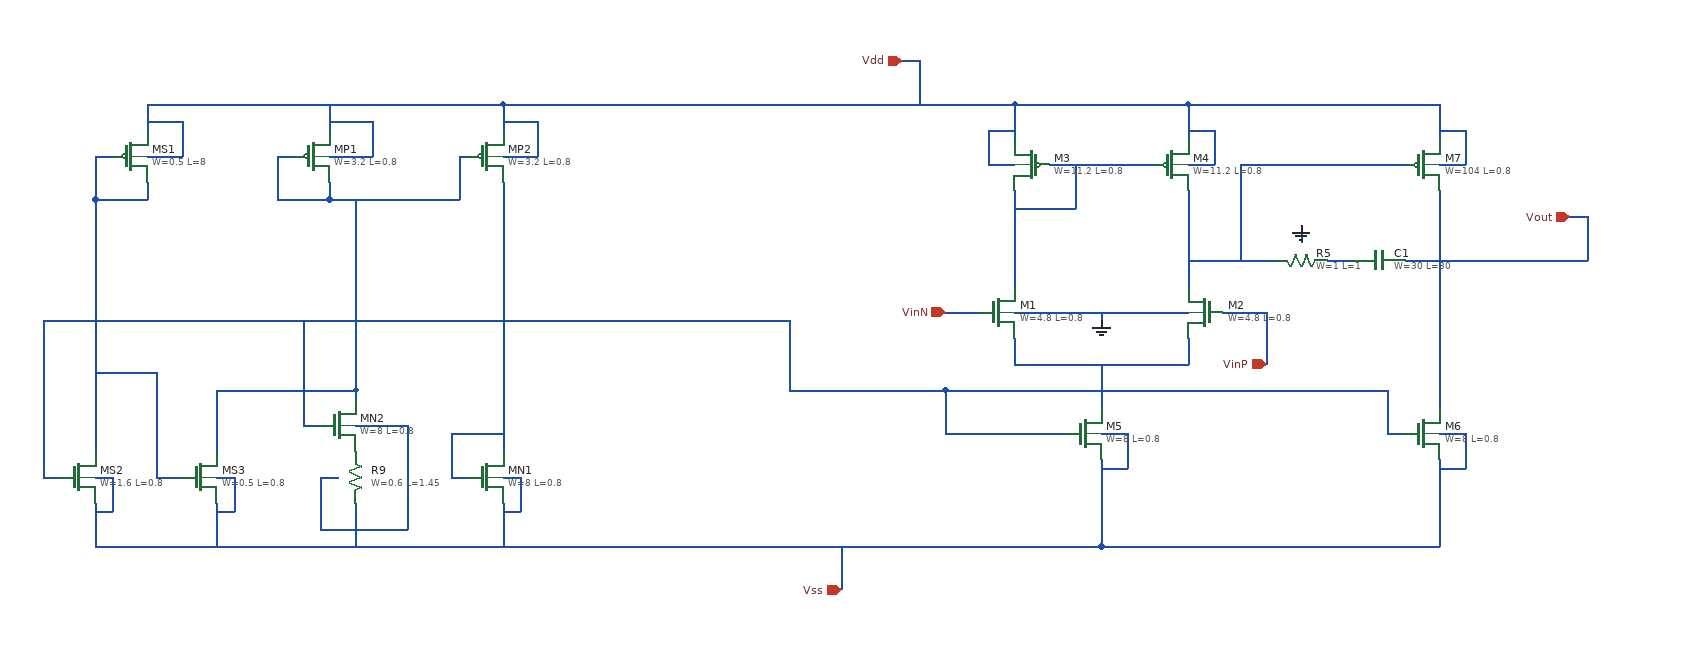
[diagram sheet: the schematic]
v {xschem version=3.4.8RC file_version=1.3}
G {}
K {}
V {}
S {}
F {}
E {}
N 270 0 270 30 {lab=#net1}
N 470 0 470 30 {lab=#net1}
N 360 30 470 30 {lab=#net1}
N 270 30 360 30 {lab=#net1}
N 370 30 370 80 {lab=#net1}
N 270 -170 270 -60 {lab=#net2}
N 470 -170 470 -60 {lab=#net3}
N 270 -270 270 -230 {lab=Vdd}
N 270 -270 470 -270 {lab=Vdd}
N 470 -270 470 -230 {lab=Vdd}
N 470 -270 670 -270 {lab=Vdd}
N 760 -270 760 -230 {lab=Vdd}
N 760 -170 760 80 {lab=Vout}
N 470 -90 570 -90 {lab=#net3}
N 720 -90 760 -90 {lab=Vout}
N 530 -200 630 -200 {lab=#net3}
N 530 -200 530 -90 {lab=#net3}
N 370 140 370 170 {lab=Vdd}
N 760 140 760 170 {lab=Vdd}
N 400 110 400 150 {lab=Vdd}
N 790 110 790 150 {lab=Vdd}
N 190 110 330 110 {lab=#net4}
N 190 70 190 110 {lab=#net4}
N 80 60 190 60 {lab=#net4}
N 190 60 610 60 {lab=#net4}
N 700 70 700 110 {lab=#net4}
N 700 110 720 110 {lab=#net4}
N 190 60 190 70 {lab=#net4}
N 700 60 700 70 {lab=#net4}
N 80 -270 270 -270 {lab=Vdd}
N 190 -30 230 -30 {lab=VinN}
N 510 -30 550 -30 {lab=VinP}
N 310 -200 430 -200 {lab=#net2}
N 340 -200 340 -150 {lab=#net2}
N 270 -150 340 -150 {lab=#net2}
N 240 -200 270 -200 {lab=Vdd}
N 240 -240 240 -200 {lab=Vdd}
N 240 -240 270 -240 {lab=Vdd}
N 470 -200 490 -200 {lab=Vdd}
N 490 -200 500 -200 {lab=Vdd}
N 500 -240 500 -200 {lab=Vdd}
N 470 -240 500 -240 {lab=Vdd}
N 270 -30 290 -30 {lab=0}
N 450 -30 470 -30 {lab=0}
N 760 -200 790 -200 {lab=Vdd}
N 790 -240 790 -200 {lab=Vdd}
N 760 -240 790 -240 {lab=Vdd}
N 370 110 400 110 {lab=Vdd}
N 370 150 400 150 {lab=Vdd}
N 760 110 790 110 {lab=Vdd}
N 760 150 790 150 {lab=Vdd}
N 670 -270 760 -270 {lab=Vdd}
N 610 60 700 60 {lab=#net4}
N 630 -200 720 -200 {lab=#net3}
N 630 -90 660 -90 {lab=#net5}
N 760 -90 930 -90 {lab=Vout}
N 930 -140 930 -90 {lab=Vout}
N 910 -140 930 -140 {lab=Vout}
N -730 -270 -320 -270 {lab=Vdd}
N -730 -270 -730 -240 {lab=Vdd}
N -520 -270 -520 -240 {lab=Vdd}
N -320 -270 -320 -240 {lab=Vdd}
N -730 -210 -690 -210 {lab=Vdd}
N -690 -250 -690 -210 {lab=Vdd}
N -730 -250 -690 -250 {lab=Vdd}
N -520 -210 -470 -210 {lab=Vdd}
N -470 -250 -470 -210 {lab=Vdd}
N -520 -250 -470 -250 {lab=Vdd}
N -320 -210 -280 -210 {lab=Vdd}
N -280 -250 -280 -210 {lab=Vdd}
N -320 -250 -280 -250 {lab=Vdd}
N -790 -210 -770 -210 {lab=#net6}
N -790 -210 -790 -160 {lab=#net6}
N -790 -160 -730 -160 {lab=#net6}
N -730 -180 -730 -160 {lab=#net6}
N -520 -180 -520 -160 {lab=#net7}
N -520 -160 -370 -160 {lab=#net7}
N -370 -210 -370 -160 {lab=#net7}
N -370 -210 -360 -210 {lab=#net7}
N -580 -210 -560 -210 {lab=#net7}
N -580 -210 -580 -160 {lab=#net7}
N -580 -160 -520 -160 {lab=#net7}
N -320 -180 -320 130 {lab=#net4}
N -790 -160 -790 130 {lab=#net6}
N -790 190 -790 240 {lab=Vdd}
N -650 190 -650 240 {lab=Vdd}
N -490 190 -490 240 {lab=Vdd}
N -320 190 -320 240 {lab=Vdd}
N -650 60 -650 130 {lab=#net7}
N -650 60 -490 60 {lab=#net7}
N -490 60 -490 70 {lab=#net7}
N -720 160 -690 160 {lab=#net6}
N -790 40 -720 40 {lab=#net6}
N -850 160 -830 160 {lab=#net4}
N -850 -20 -850 160 {lab=#net4}
N -850 -20 -320 -20 {lab=#net4}
N -550 100 -530 100 {lab=#net4}
N -550 -20 -550 100 {lab=#net4}
N -790 160 -770 160 {lab=Vdd}
N -770 160 -770 200 {lab=Vdd}
N -790 200 -770 200 {lab=Vdd}
N -650 160 -630 160 {lab=Vdd}
N -630 160 -630 200 {lab=Vdd}
N -650 200 -630 200 {lab=Vdd}
N -320 160 -300 160 {lab=Vdd}
N -300 160 -300 200 {lab=Vdd}
N -320 200 -300 200 {lab=Vdd}
N -490 100 -430 100 {lab=Vdd}
N -430 100 -430 220 {lab=Vdd}
N -490 220 -430 220 {lab=Vdd}
N -380 160 -360 160 {lab=#net4}
N -380 110 -380 160 {lab=#net4}
N -380 110 -320 110 {lab=#net4}
N -720 40 -720 160 {lab=#net6}
N -490 -160 -490 60 {lab=#net7}
N -320 -20 10 -20 {lab=#net4}
N 10 10 10 60 {lab=#net4}
N 10 60 80 60 {lab=#net4}
N 600 -130 600 -110 {lab=0}
N -530 160 -510 160 {lab=Vdd}
N -530 160 -530 220 {lab=Vdd}
N -530 220 -490 220 {lab=Vdd}
N 290 -30 450 -30 {lab=0}
N 370 -30 370 -20 {lab=0}
N 140 -320 160 -320 {lab=Vdd}
N 160 -320 160 -270 {lab=Vdd}
N -320 -270 80 -270 {lab=Vdd}
N 10 -20 10 10 {lab=#net4}
N -790 240 370 240 {lab=Vdd}
N 370 170 370 240 {lab=Vdd}
N 370 240 760 240 {lab=Vdd}
N 760 170 760 240 {lab=Vdd}
N 560 -30 560 30 {lab=VinP}
N 550 -30 560 -30 {lab=VinP}
N 70 240 70 290 {lab=Vdd}
C {/foss/pdks/sky130A/libs.tech/xschem/sky130_fd_pr/nfet_01v8_lvt.sym} 250 -30 0 0 {name=M1
W=4.8
L=0.8
nf=1
mult=1
ad="expr('int((@nf + 1)/2) * @W / @nf * 0.29')"
pd="expr('2*int((@nf + 1)/2) * (@W / @nf + 0.29)')"
as="expr('int((@nf + 2)/2) * @W / @nf * 0.29')"
ps="expr('2*int((@nf + 2)/2) * (@W / @nf + 0.29)')"
nrd="expr('0.29 / @W ')" nrs="expr('0.29 / @W ')"
sa=0 sb=0 sd=0
model=nfet_01v8_lvt
spiceprefix=X
}
C {sky130_fd_pr/pfet_01v8.sym} 290 -200 0 1 {name=M3
W=11.2
L=0.8
nf=1
mult=1
ad="expr('int((@nf + 1)/2) * @W / @nf * 0.29')"
pd="expr('2*int((@nf + 1)/2) * (@W / @nf + 0.29)')"
as="expr('int((@nf + 2)/2) * @W / @nf * 0.29')"
ps="expr('2*int((@nf + 2)/2) * (@W / @nf + 0.29)')"
nrd="expr('0.29 / @W ')" nrs="expr('0.29 / @W ')"
sa=0 sb=0 sd=0
model=pfet_01v8
spiceprefix=X
}
C {sky130_fd_pr/nfet_01v8.sym} 350 110 0 0 {name=M5
W=8
L=0.8
nf=1 
mult=3
ad="expr('int((@nf + 1)/2) * @W / @nf * 0.29')"
pd="expr('2*int((@nf + 1)/2) * (@W / @nf + 0.29)')"
as="expr('int((@nf + 2)/2) * @W / @nf * 0.29')"
ps="expr('2*int((@nf + 2)/2) * (@W / @nf + 0.29)')"
nrd="expr('0.29 / @W ')" nrs="expr('0.29 / @W ')"
sa=0 sb=0 sd=0
model=nfet_01v8
spiceprefix=X
}
C {/foss/pdks/sky130A/libs.tech/xschem/sky130_fd_pr/nfet_01v8_lvt.sym} 490 -30 0 1 {name=M2
W=4.8
L=0.8
nf=1
mult=1
ad="expr('int((@nf + 1)/2) * @W / @nf * 0.29')"
pd="expr('2*int((@nf + 1)/2) * (@W / @nf + 0.29)')"
as="expr('int((@nf + 2)/2) * @W / @nf * 0.29')"
ps="expr('2*int((@nf + 2)/2) * (@W / @nf + 0.29)')"
nrd="expr('0.29 / @W ')" nrs="expr('0.29 / @W ')"
sa=0 sb=0 sd=0
model=nfet_01v8_lvt
spiceprefix=X
}
C {sky130_fd_pr/pfet_01v8.sym} 450 -200 0 0 {name=M4
W=11.2
L=0.8
nf=1
mult=1
ad="expr('int((@nf + 1)/2) * @W / @nf * 0.29')"
pd="expr('2*int((@nf + 1)/2) * (@W / @nf + 0.29)')"
as="expr('int((@nf + 2)/2) * @W / @nf * 0.29')"
ps="expr('2*int((@nf + 2)/2) * (@W / @nf + 0.29)')"
nrd="expr('0.29 / @W ')" nrs="expr('0.29 / @W ')"
sa=0 sb=0 sd=0
model=pfet_01v8
spiceprefix=X
}
C {sky130_fd_pr/nfet_01v8.sym} 740 110 0 0 {name=M6
W=8
L=0.8
nf=1
mult=13
ad="expr('int((@nf + 1)/2) * @W / @nf * 0.29')"
pd="expr('2*int((@nf + 1)/2) * (@W / @nf + 0.29)')"
as="expr('int((@nf + 2)/2) * @W / @nf * 0.29')"
ps="expr('2*int((@nf + 2)/2) * (@W / @nf + 0.29)')"
nrd="expr('0.29 / @W ')" nrs="expr('0.29 / @W ')"
sa=0 sb=0 sd=0
model=nfet_01v8
spiceprefix=X
}
C {sky130_fd_pr/pfet_01v8.sym} 740 -200 0 0 {name=M7
W=104
L=0.8
nf=14
mult=1
ad="expr('int((@nf + 1)/2) * @W / @nf * 0.29')"
pd="expr('2*int((@nf + 1)/2) * (@W / @nf + 0.29)')"
as="expr('int((@nf + 2)/2) * @W / @nf * 0.29')"
ps="expr('2*int((@nf + 2)/2) * (@W / @nf + 0.29)')"
nrd="expr('0.29 / @W ')" nrs="expr('0.29 / @W ')"
sa=0 sb=0 sd=0
model=pfet_01v8
spiceprefix=X
}
C {sky130_fd_pr/cap_mim_m3_1.sym} 690 -90 3 0 {name=C1 model=cap_mim_m3_1 W=30 L=30 MF=1 spiceprefix=X}
C {sky130_fd_pr/res_high_po.sym} 600 -90 1 0 {name=R5
W=1
L=1
model=res_high_po
spiceprefix=X
mult=1}
C {sky130_fd_pr/pfet_01v8.sym} -750 -210 0 0 {name=MS1
W=0.5
L=8
nf=1
mult=1
ad="expr('int((@nf + 1)/2) * @W / @nf * 0.29')"
pd="expr('2*int((@nf + 1)/2) * (@W / @nf + 0.29)')"
as="expr('int((@nf + 2)/2) * @W / @nf * 0.29')"
ps="expr('2*int((@nf + 2)/2) * (@W / @nf + 0.29)')"
nrd="expr('0.29 / @W ')" nrs="expr('0.29 / @W ')"
sa=0 sb=0 sd=0
model=pfet_01v8
spiceprefix=X
}
C {sky130_fd_pr/pfet_01v8.sym} -540 -210 0 0 {name=MP1
W=3.2
L=0.8
nf=1
mult=1
ad="expr('int((@nf + 1)/2) * @W / @nf * 0.29')"
pd="expr('2*int((@nf + 1)/2) * (@W / @nf + 0.29)')"
as="expr('int((@nf + 2)/2) * @W / @nf * 0.29')"
ps="expr('2*int((@nf + 2)/2) * (@W / @nf + 0.29)')"
nrd="expr('0.29 / @W ')" nrs="expr('0.29 / @W ')"
sa=0 sb=0 sd=0
model=pfet_01v8
spiceprefix=X
}
C {sky130_fd_pr/pfet_01v8.sym} -340 -210 0 0 {name=MP2
W=3.2
L=0.8
nf=1
mult=1
ad="expr('int((@nf + 1)/2) * @W / @nf * 0.29')"
pd="expr('2*int((@nf + 1)/2) * (@W / @nf + 0.29)')"
as="expr('int((@nf + 2)/2) * @W / @nf * 0.29')"
ps="expr('2*int((@nf + 2)/2) * (@W / @nf + 0.29)')"
nrd="expr('0.29 / @W ')" nrs="expr('0.29 / @W ')"
sa=0 sb=0 sd=0
model=pfet_01v8
spiceprefix=X
}
C {sky130_fd_pr/res_xhigh_po.sym} -490 160 0 0 {name=R9
W=0.6
L=1.45
model=res_xhigh_po
spiceprefix=X
 mult=1}
C {sky130_fd_pr/nfet_01v8.sym} -810 160 0 0 {name=MS2
W=1.6
L=0.8
nf=1 
mult=1
ad="expr('int((@nf + 1)/2) * @W / @nf * 0.29')"
pd="expr('2*int((@nf + 1)/2) * (@W / @nf + 0.29)')"
as="expr('int((@nf + 2)/2) * @W / @nf * 0.29')"
ps="expr('2*int((@nf + 2)/2) * (@W / @nf + 0.29)')"
nrd="expr('0.29 / @W ')" nrs="expr('0.29 / @W ')"
sa=0 sb=0 sd=0
model=nfet_01v8
spiceprefix=X
}
C {sky130_fd_pr/nfet_01v8.sym} -670 160 0 0 {name=MS3
W=0.5
L=0.8
nf=1 
mult=1
ad="expr('int((@nf + 1)/2) * @W / @nf * 0.29')"
pd="expr('2*int((@nf + 1)/2) * (@W / @nf + 0.29)')"
as="expr('int((@nf + 2)/2) * @W / @nf * 0.29')"
ps="expr('2*int((@nf + 2)/2) * (@W / @nf + 0.29)')"
nrd="expr('0.29 / @W ')" nrs="expr('0.29 / @W ')"
sa=0 sb=0 sd=0
model=nfet_01v8
spiceprefix=X
}
C {sky130_fd_pr/nfet_01v8.sym} -510 100 0 0 {name=MN2
W=8
L=0.8
nf=1 
mult=4
ad="expr('int((@nf + 1)/2) * @W / @nf * 0.29')"
pd="expr('2*int((@nf + 1)/2) * (@W / @nf + 0.29)')"
as="expr('int((@nf + 2)/2) * @W / @nf * 0.29')"
ps="expr('2*int((@nf + 2)/2) * (@W / @nf + 0.29)')"
nrd="expr('0.29 / @W ')" nrs="expr('0.29 / @W ')"
sa=0 sb=0 sd=0
model=nfet_01v8
spiceprefix=X
}
C {sky130_fd_pr/nfet_01v8.sym} -340 160 0 0 {name=MN1
W=8
L=0.8
nf=1 
mult=1
ad="expr('int((@nf + 1)/2) * @W / @nf * 0.29')"
pd="expr('2*int((@nf + 1)/2) * (@W / @nf + 0.29)')"
as="expr('int((@nf + 2)/2) * @W / @nf * 0.29')"
ps="expr('2*int((@nf + 2)/2) * (@W / @nf + 0.29)')"
nrd="expr('0.29 / @W ')" nrs="expr('0.29 / @W ')"
sa=0 sb=0 sd=0
model=nfet_01v8
spiceprefix=X
}
C {gnd.sym} 600 -130 2 0 {name=l3 lab=0}
C {gnd.sym} 370 -20 0 0 {name=l12 lab=0}
C {ipin.sym} 140 -320 0 0 {name=p1 lab=Vdd}
C {ipin.sym} 190 -30 0 0 {name=p2 lab=VinN}
C {ipin.sym} 560 30 0 0 {name=p4 lab=VinP}
C {ipin.sym} 910 -140 0 0 {name=p5 lab=Vout}
C {ipin.sym} 70 290 0 0 {name=p3 lab=Vss}
